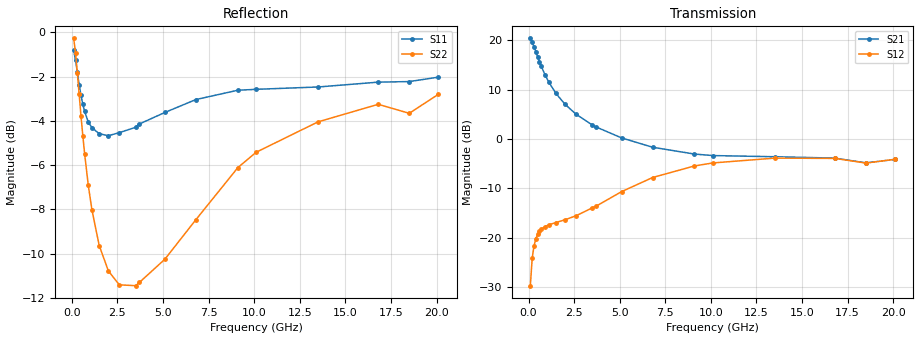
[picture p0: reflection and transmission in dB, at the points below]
!  Infineon Technologies AG
! BFR380L3 , PF131585-7, No.6, Th 09.10.01, soldered on pcb-board, measured with PP GSG850
!  Vce=1.5 V,  Ic=3.0 mA
! Common Emitter S-Parameters:  15. November 2001
#  GHz  S  MA  R  50
! f  S11  S21  S12  S22
! GHz  Mag  Ang  Mag  Ang  Mag  Ang  Mag  Ang
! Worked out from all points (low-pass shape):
!   201 points, 100 MHz to 20.1 GHz, reference 50 ohm
!   highest |S21| = 20.35 dB at 100 MHz (marker M1); lowest = -4.8 dB at 18.5 GHz (marker M2)
!   |S21| within 3 dB of the highest: start of sweep to 431.3 MHz
!   lowest |S11| = -4.7 dB at 2 GHz (marker M3), VSWR 3.81, Z = 13.1 - j1.25 ohm
!   |S11| at or under -10 dB: nowhere
!   |S22| runs from -11.6 to -0.3 dB; largest |S21 - S12| = 10
!   S11 on the Smith chart (normalised r, x): 100 MHz: 1.14, -4.69; 400 MHz: 0.32, -1.15; 1.1 GHz: 0.27, -0.32; 3.7 GHz: 0.25, +0.28; 9.1 GHz: 0.33, +1.06; 20.1 GHz: 0.97, +2.55
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0.1  0.9101 -22.8  10.41 164.4  0.03285 77.2  0.9688 -13.6
0.2  0.8648 -44.5  9.553 150.6  0.06189 66.0  0.899 -25.7
0.3  0.8127 -63.3  8.597 138.8  0.08295 57.0  0.8107 -35.7
0.4  0.7604 -79.4  7.65 128.9  0.0979 50.1  0.724 -43.6
0.5  0.7211 -92.9  6.782 120.9  0.1087 45.1  0.6482 -49.7
0.6  0.6877 -104.3  6.043 114.2  0.1164 41.2  0.5845 -54.6
0.7  0.6624 -114.2  5.43 108.5  0.1221 38.4  0.5314 -58.5
0.9  0.627 -130.0  4.471 99.3  0.1298 34.9  0.4515 -64.5
1.1  0.6088 -142.3  3.791 92.0  0.1353 33.1  0.3971 -69.2
1.5  0.5899 -160.5  2.896 80.3  0.1429 32.6  0.3298 -76.4
2  0.584 -176.9  2.243 68.7  0.1525 34.5  0.2891 -84.5
2.6  0.5931 168.3  1.785 57.3  0.1672 38.5  0.2688 -94.9
3.5  0.6101 150.3  1.384 42.7  0.2012 43.6  0.2676 -111.2
3.7  0.6205 147.4  1.324 40.2  0.2089 44.2  0.2721 -115.8
5.1  0.6589 125.9  1.026 23.2  0.2933 44.7  0.3071 -143.2
6.8  0.7047 105.0  0.825 9.3  0.4075 37.0  0.3772 -176.4
9.1  0.7397 83.7  0.7041 -1.9  0.5339 20.6  0.4944 148.8
10.1  0.7432 76.5  0.6798 -5.7  0.5723 13.3  0.5356 135.5
13.5  0.7523 58.5  0.6614 -19.3  0.6406 -9.8  0.6275 100.9
16.8  0.7715 46.9  0.6407 -31.2  0.6362 -26.3  0.6875 77.4
18.5  0.7738 45.4  0.5729 -38.7  0.5707 -34.8  0.656 71.5
20.1  0.7918 38.3  0.622 -43.0  0.6234 -39.9  0.7243 60.6
